VERSION 5.7 ;
  NOWIREEXTENSIONATPIN ON ;
  DIVIDERCHAR "/" ;
  BUSBITCHARS "[]" ;
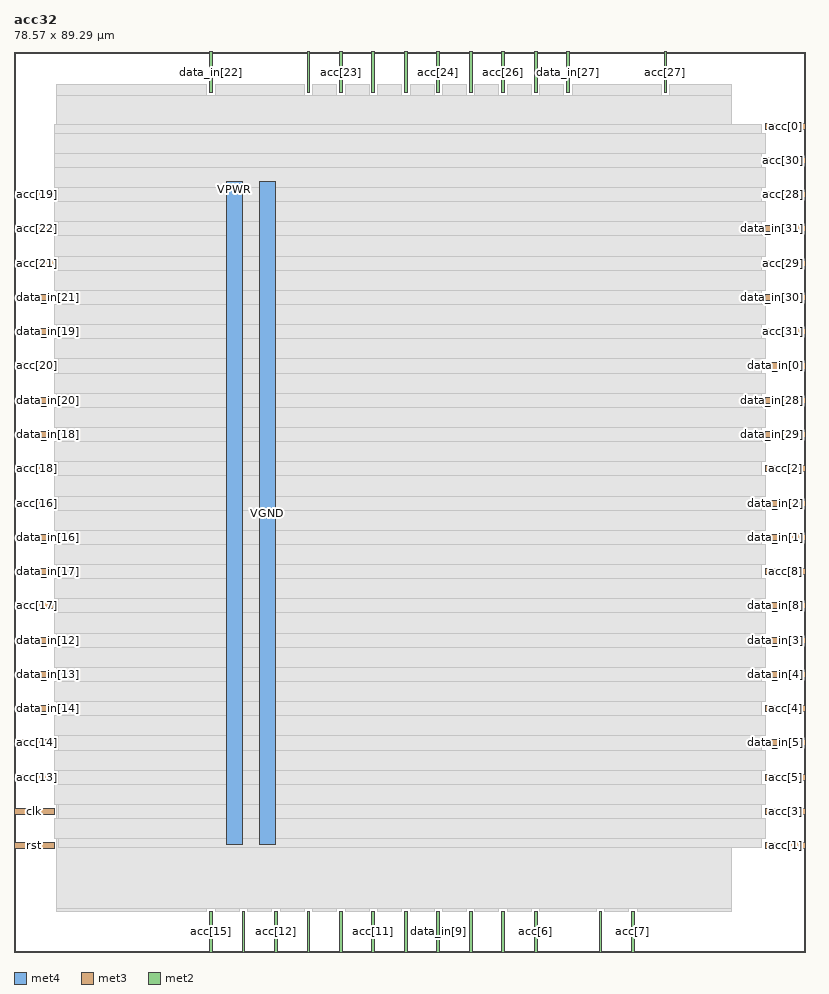
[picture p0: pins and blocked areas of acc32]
MACRO acc32
  CLASS BLOCK ;
  FOREIGN acc32 ;
  ORIGIN 0.000 0.000 ;
  SIZE 78.570 BY 89.290 ;
  PIN VGND
    DIRECTION INOUT ;
    USE GROUND ;
    PORT
      LAYER met4 ;
        RECT 24.340 10.640 25.940 76.400 ;
    END
  END VGND
  PIN VPWR
    DIRECTION INOUT ;
    USE POWER ;
    PORT
      LAYER met4 ;
        RECT 21.040 10.640 22.640 76.400 ;
    END
  END VPWR
  PIN acc[0]
    DIRECTION OUTPUT ;
    USE SIGNAL ;
    ANTENNADIFFAREA 0.445500 ;
    PORT
      LAYER met3 ;
        RECT 74.570 81.640 78.570 82.240 ;
    END
  END acc[0]
  PIN acc[10]
    DIRECTION OUTPUT ;
    USE SIGNAL ;
    ANTENNADIFFAREA 0.445500 ;
    PORT
      LAYER met2 ;
        RECT 29.070 0.000 29.350 4.000 ;
    END
  END acc[10]
  PIN acc[11]
    DIRECTION OUTPUT ;
    USE SIGNAL ;
    ANTENNADIFFAREA 0.445500 ;
    PORT
      LAYER met2 ;
        RECT 35.510 0.000 35.790 4.000 ;
    END
  END acc[11]
  PIN acc[12]
    DIRECTION OUTPUT ;
    USE SIGNAL ;
    ANTENNADIFFAREA 0.445500 ;
    PORT
      LAYER met2 ;
        RECT 25.850 0.000 26.130 4.000 ;
    END
  END acc[12]
  PIN acc[13]
    DIRECTION OUTPUT ;
    USE SIGNAL ;
    ANTENNADIFFAREA 0.445500 ;
    PORT
      LAYER met3 ;
        RECT 0.000 17.040 4.000 17.640 ;
    END
  END acc[13]
  PIN acc[14]
    DIRECTION OUTPUT ;
    USE SIGNAL ;
    ANTENNADIFFAREA 0.445500 ;
    PORT
      LAYER met3 ;
        RECT 0.000 20.440 4.000 21.040 ;
    END
  END acc[14]
  PIN acc[15]
    DIRECTION OUTPUT ;
    USE SIGNAL ;
    ANTENNADIFFAREA 0.445500 ;
    PORT
      LAYER met2 ;
        RECT 19.410 0.000 19.690 4.000 ;
    END
  END acc[15]
  PIN acc[16]
    DIRECTION OUTPUT ;
    USE SIGNAL ;
    ANTENNADIFFAREA 0.445500 ;
    PORT
      LAYER met3 ;
        RECT 0.000 44.240 4.000 44.840 ;
    END
  END acc[16]
  PIN acc[17]
    DIRECTION OUTPUT ;
    USE SIGNAL ;
    ANTENNADIFFAREA 0.445500 ;
    PORT
      LAYER met3 ;
        RECT 0.000 34.040 4.000 34.640 ;
    END
  END acc[17]
  PIN acc[18]
    DIRECTION OUTPUT ;
    USE SIGNAL ;
    ANTENNADIFFAREA 0.445500 ;
    PORT
      LAYER met3 ;
        RECT 0.000 47.640 4.000 48.240 ;
    END
  END acc[18]
  PIN acc[19]
    DIRECTION OUTPUT ;
    USE SIGNAL ;
    ANTENNADIFFAREA 0.445500 ;
    PORT
      LAYER met3 ;
        RECT 0.000 74.840 4.000 75.440 ;
    END
  END acc[19]
  PIN acc[1]
    DIRECTION OUTPUT ;
    USE SIGNAL ;
    ANTENNADIFFAREA 0.445500 ;
    PORT
      LAYER met3 ;
        RECT 74.570 10.240 78.570 10.840 ;
    END
  END acc[1]
  PIN acc[20]
    DIRECTION OUTPUT ;
    USE SIGNAL ;
    ANTENNADIFFAREA 0.445500 ;
    PORT
      LAYER met3 ;
        RECT 0.000 57.840 4.000 58.440 ;
    END
  END acc[20]
  PIN acc[21]
    DIRECTION OUTPUT ;
    USE SIGNAL ;
    ANTENNADIFFAREA 0.445500 ;
    PORT
      LAYER met3 ;
        RECT 0.000 68.040 4.000 68.640 ;
    END
  END acc[21]
  PIN acc[22]
    DIRECTION OUTPUT ;
    USE SIGNAL ;
    ANTENNADIFFAREA 0.445500 ;
    PORT
      LAYER met3 ;
        RECT 0.000 71.440 4.000 72.040 ;
    END
  END acc[22]
  PIN acc[23]
    DIRECTION OUTPUT ;
    USE SIGNAL ;
    ANTENNADIFFAREA 0.445500 ;
    PORT
      LAYER met2 ;
        RECT 32.290 85.290 32.570 89.290 ;
    END
  END acc[23]
  PIN acc[24]
    DIRECTION OUTPUT ;
    USE SIGNAL ;
    ANTENNADIFFAREA 0.445500 ;
    PORT
      LAYER met2 ;
        RECT 41.950 85.290 42.230 89.290 ;
    END
  END acc[24]
  PIN acc[25]
    DIRECTION OUTPUT ;
    USE SIGNAL ;
    ANTENNADIFFAREA 0.445500 ;
    PORT
      LAYER met2 ;
        RECT 35.510 85.290 35.790 89.290 ;
    END
  END acc[25]
  PIN acc[26]
    DIRECTION OUTPUT ;
    USE SIGNAL ;
    ANTENNADIFFAREA 0.445500 ;
    PORT
      LAYER met2 ;
        RECT 48.390 85.290 48.670 89.290 ;
    END
  END acc[26]
  PIN acc[27]
    DIRECTION OUTPUT ;
    USE SIGNAL ;
    ANTENNADIFFAREA 0.445500 ;
    PORT
      LAYER met2 ;
        RECT 64.490 85.290 64.770 89.290 ;
    END
  END acc[27]
  PIN acc[28]
    DIRECTION OUTPUT ;
    USE SIGNAL ;
    ANTENNADIFFAREA 0.445500 ;
    PORT
      LAYER met3 ;
        RECT 74.570 74.840 78.570 75.440 ;
    END
  END acc[28]
  PIN acc[29]
    DIRECTION OUTPUT ;
    USE SIGNAL ;
    ANTENNADIFFAREA 0.445500 ;
    PORT
      LAYER met3 ;
        RECT 74.570 68.040 78.570 68.640 ;
    END
  END acc[29]
  PIN acc[2]
    DIRECTION OUTPUT ;
    USE SIGNAL ;
    ANTENNADIFFAREA 0.445500 ;
    PORT
      LAYER met3 ;
        RECT 74.570 47.640 78.570 48.240 ;
    END
  END acc[2]
  PIN acc[30]
    DIRECTION OUTPUT ;
    USE SIGNAL ;
    ANTENNADIFFAREA 0.445500 ;
    PORT
      LAYER met3 ;
        RECT 74.570 78.240 78.570 78.840 ;
    END
  END acc[30]
  PIN acc[31]
    DIRECTION OUTPUT ;
    USE SIGNAL ;
    ANTENNADIFFAREA 0.445500 ;
    PORT
      LAYER met3 ;
        RECT 74.570 61.240 78.570 61.840 ;
    END
  END acc[31]
  PIN acc[3]
    DIRECTION OUTPUT ;
    USE SIGNAL ;
    ANTENNADIFFAREA 0.445500 ;
    PORT
      LAYER met3 ;
        RECT 74.570 13.640 78.570 14.240 ;
    END
  END acc[3]
  PIN acc[4]
    DIRECTION OUTPUT ;
    USE SIGNAL ;
    ANTENNADIFFAREA 0.445500 ;
    PORT
      LAYER met3 ;
        RECT 74.570 23.840 78.570 24.440 ;
    END
  END acc[4]
  PIN acc[5]
    DIRECTION OUTPUT ;
    USE SIGNAL ;
    ANTENNADIFFAREA 0.445500 ;
    PORT
      LAYER met3 ;
        RECT 74.570 17.040 78.570 17.640 ;
    END
  END acc[5]
  PIN acc[6]
    DIRECTION OUTPUT ;
    USE SIGNAL ;
    ANTENNADIFFAREA 0.445500 ;
    PORT
      LAYER met2 ;
        RECT 51.610 0.000 51.890 4.000 ;
    END
  END acc[6]
  PIN acc[7]
    DIRECTION OUTPUT ;
    USE SIGNAL ;
    ANTENNADIFFAREA 0.445500 ;
    PORT
      LAYER met2 ;
        RECT 61.270 0.000 61.550 4.000 ;
    END
  END acc[7]
  PIN acc[8]
    DIRECTION OUTPUT ;
    USE SIGNAL ;
    ANTENNADIFFAREA 0.445500 ;
    PORT
      LAYER met3 ;
        RECT 74.570 37.440 78.570 38.040 ;
    END
  END acc[8]
  PIN acc[9]
    DIRECTION OUTPUT ;
    USE SIGNAL ;
    ANTENNADIFFAREA 0.445500 ;
    PORT
      LAYER met2 ;
        RECT 45.170 0.000 45.450 4.000 ;
    END
  END acc[9]
  PIN clk
    DIRECTION INPUT ;
    USE SIGNAL ;
    ANTENNAGATEAREA 0.852000 ;
    PORT
      LAYER met3 ;
        RECT 0.000 13.640 4.000 14.240 ;
    END
  END clk
  PIN data_in[0]
    DIRECTION INPUT ;
    USE SIGNAL ;
    ANTENNAGATEAREA 0.196500 ;
    PORT
      LAYER met3 ;
        RECT 74.570 57.840 78.570 58.440 ;
    END
  END data_in[0]
  PIN data_in[10]
    DIRECTION INPUT ;
    USE SIGNAL ;
    ANTENNAGATEAREA 0.196500 ;
    PORT
      LAYER met2 ;
        RECT 32.290 0.000 32.570 4.000 ;
    END
  END data_in[10]
  PIN data_in[11]
    DIRECTION INPUT ;
    USE SIGNAL ;
    ANTENNAGATEAREA 0.196500 ;
    PORT
      LAYER met2 ;
        RECT 38.730 0.000 39.010 4.000 ;
    END
  END data_in[11]
  PIN data_in[12]
    DIRECTION INPUT ;
    USE SIGNAL ;
    ANTENNAGATEAREA 0.196500 ;
    PORT
      LAYER met3 ;
        RECT 0.000 30.640 4.000 31.240 ;
    END
  END data_in[12]
  PIN data_in[13]
    DIRECTION INPUT ;
    USE SIGNAL ;
    ANTENNAGATEAREA 0.196500 ;
    PORT
      LAYER met3 ;
        RECT 0.000 27.240 4.000 27.840 ;
    END
  END data_in[13]
  PIN data_in[14]
    DIRECTION INPUT ;
    USE SIGNAL ;
    ANTENNAGATEAREA 0.196500 ;
    PORT
      LAYER met3 ;
        RECT 0.000 23.840 4.000 24.440 ;
    END
  END data_in[14]
  PIN data_in[15]
    DIRECTION INPUT ;
    USE SIGNAL ;
    ANTENNAGATEAREA 0.196500 ;
    PORT
      LAYER met2 ;
        RECT 22.630 0.000 22.910 4.000 ;
    END
  END data_in[15]
  PIN data_in[16]
    DIRECTION INPUT ;
    USE SIGNAL ;
    ANTENNAGATEAREA 0.196500 ;
    PORT
      LAYER met3 ;
        RECT 0.000 40.840 4.000 41.440 ;
    END
  END data_in[16]
  PIN data_in[17]
    DIRECTION INPUT ;
    USE SIGNAL ;
    ANTENNAGATEAREA 0.196500 ;
    PORT
      LAYER met3 ;
        RECT 0.000 37.440 4.000 38.040 ;
    END
  END data_in[17]
  PIN data_in[18]
    DIRECTION INPUT ;
    USE SIGNAL ;
    ANTENNAGATEAREA 0.196500 ;
    PORT
      LAYER met3 ;
        RECT 0.000 51.040 4.000 51.640 ;
    END
  END data_in[18]
  PIN data_in[19]
    DIRECTION INPUT ;
    USE SIGNAL ;
    ANTENNAGATEAREA 0.196500 ;
    PORT
      LAYER met3 ;
        RECT 0.000 61.240 4.000 61.840 ;
    END
  END data_in[19]
  PIN data_in[1]
    DIRECTION INPUT ;
    USE SIGNAL ;
    ANTENNAGATEAREA 0.196500 ;
    PORT
      LAYER met3 ;
        RECT 74.570 40.840 78.570 41.440 ;
    END
  END data_in[1]
  PIN data_in[20]
    DIRECTION INPUT ;
    USE SIGNAL ;
    ANTENNAGATEAREA 0.196500 ;
    PORT
      LAYER met3 ;
        RECT 0.000 54.440 4.000 55.040 ;
    END
  END data_in[20]
  PIN data_in[21]
    DIRECTION INPUT ;
    USE SIGNAL ;
    ANTENNAGATEAREA 0.196500 ;
    PORT
      LAYER met3 ;
        RECT 0.000 64.640 4.000 65.240 ;
    END
  END data_in[21]
  PIN data_in[22]
    DIRECTION INPUT ;
    USE SIGNAL ;
    ANTENNAGATEAREA 0.196500 ;
    PORT
      LAYER met2 ;
        RECT 19.410 85.290 19.690 89.290 ;
    END
  END data_in[22]
  PIN data_in[23]
    DIRECTION INPUT ;
    USE SIGNAL ;
    ANTENNAGATEAREA 0.196500 ;
    PORT
      LAYER met2 ;
        RECT 29.070 85.290 29.350 89.290 ;
    END
  END data_in[23]
  PIN data_in[24]
    DIRECTION INPUT ;
    USE SIGNAL ;
    ANTENNAGATEAREA 0.196500 ;
    PORT
      LAYER met2 ;
        RECT 45.170 85.290 45.450 89.290 ;
    END
  END data_in[24]
  PIN data_in[25]
    DIRECTION INPUT ;
    USE SIGNAL ;
    ANTENNAGATEAREA 0.196500 ;
    PORT
      LAYER met2 ;
        RECT 38.730 85.290 39.010 89.290 ;
    END
  END data_in[25]
  PIN data_in[26]
    DIRECTION INPUT ;
    USE SIGNAL ;
    ANTENNAGATEAREA 0.196500 ;
    PORT
      LAYER met2 ;
        RECT 51.610 85.290 51.890 89.290 ;
    END
  END data_in[26]
  PIN data_in[27]
    DIRECTION INPUT ;
    USE SIGNAL ;
    ANTENNAGATEAREA 0.196500 ;
    PORT
      LAYER met2 ;
        RECT 54.830 85.290 55.110 89.290 ;
    END
  END data_in[27]
  PIN data_in[28]
    DIRECTION INPUT ;
    USE SIGNAL ;
    ANTENNAGATEAREA 0.196500 ;
    PORT
      LAYER met3 ;
        RECT 74.570 54.440 78.570 55.040 ;
    END
  END data_in[28]
  PIN data_in[29]
    DIRECTION INPUT ;
    USE SIGNAL ;
    ANTENNAGATEAREA 0.196500 ;
    PORT
      LAYER met3 ;
        RECT 74.570 51.040 78.570 51.640 ;
    END
  END data_in[29]
  PIN data_in[2]
    DIRECTION INPUT ;
    USE SIGNAL ;
    ANTENNAGATEAREA 0.196500 ;
    PORT
      LAYER met3 ;
        RECT 74.570 44.240 78.570 44.840 ;
    END
  END data_in[2]
  PIN data_in[30]
    DIRECTION INPUT ;
    USE SIGNAL ;
    ANTENNAGATEAREA 0.196500 ;
    PORT
      LAYER met3 ;
        RECT 74.570 64.640 78.570 65.240 ;
    END
  END data_in[30]
  PIN data_in[31]
    DIRECTION INPUT ;
    USE SIGNAL ;
    ANTENNAGATEAREA 0.196500 ;
    PORT
      LAYER met3 ;
        RECT 74.570 71.440 78.570 72.040 ;
    END
  END data_in[31]
  PIN data_in[3]
    DIRECTION INPUT ;
    USE SIGNAL ;
    ANTENNAGATEAREA 0.213000 ;
    PORT
      LAYER met3 ;
        RECT 74.570 30.640 78.570 31.240 ;
    END
  END data_in[3]
  PIN data_in[4]
    DIRECTION INPUT ;
    USE SIGNAL ;
    ANTENNAGATEAREA 0.196500 ;
    PORT
      LAYER met3 ;
        RECT 74.570 27.240 78.570 27.840 ;
    END
  END data_in[4]
  PIN data_in[5]
    DIRECTION INPUT ;
    USE SIGNAL ;
    ANTENNAGATEAREA 0.196500 ;
    PORT
      LAYER met3 ;
        RECT 74.570 20.440 78.570 21.040 ;
    END
  END data_in[5]
  PIN data_in[6]
    DIRECTION INPUT ;
    USE SIGNAL ;
    ANTENNAGATEAREA 0.196500 ;
    PORT
      LAYER met2 ;
        RECT 48.390 0.000 48.670 4.000 ;
    END
  END data_in[6]
  PIN data_in[7]
    DIRECTION INPUT ;
    USE SIGNAL ;
    ANTENNAGATEAREA 0.196500 ;
    PORT
      LAYER met2 ;
        RECT 58.050 0.000 58.330 4.000 ;
    END
  END data_in[7]
  PIN data_in[8]
    DIRECTION INPUT ;
    USE SIGNAL ;
    ANTENNAGATEAREA 0.196500 ;
    PORT
      LAYER met3 ;
        RECT 74.570 34.040 78.570 34.640 ;
    END
  END data_in[8]
  PIN data_in[9]
    DIRECTION INPUT ;
    USE SIGNAL ;
    ANTENNAGATEAREA 0.196500 ;
    PORT
      LAYER met2 ;
        RECT 41.950 0.000 42.230 4.000 ;
    END
  END data_in[9]
  PIN rst
    DIRECTION INPUT ;
    USE SIGNAL ;
    ANTENNAGATEAREA 0.126000 ;
    PORT
      LAYER met3 ;
        RECT 0.000 10.240 4.000 10.840 ;
    END
  END rst
  OBS
      LAYER nwell ;
        RECT 5.330 10.795 72.870 76.245 ;
      LAYER li1 ;
        RECT 5.520 10.795 72.680 76.245 ;
      LAYER met1 ;
        RECT 4.210 10.640 72.680 76.400 ;
      LAYER met2 ;
        RECT 4.230 85.010 19.130 86.090 ;
        RECT 19.970 85.010 28.790 86.090 ;
        RECT 29.630 85.010 32.010 86.090 ;
        RECT 32.850 85.010 35.230 86.090 ;
        RECT 36.070 85.010 38.450 86.090 ;
        RECT 39.290 85.010 41.670 86.090 ;
        RECT 42.510 85.010 44.890 86.090 ;
        RECT 45.730 85.010 48.110 86.090 ;
        RECT 48.950 85.010 51.330 86.090 ;
        RECT 52.170 85.010 54.550 86.090 ;
        RECT 55.390 85.010 64.210 86.090 ;
        RECT 65.050 85.010 71.210 86.090 ;
        RECT 4.230 4.280 71.210 85.010 ;
        RECT 4.230 4.000 19.130 4.280 ;
        RECT 19.970 4.000 22.350 4.280 ;
        RECT 23.190 4.000 25.570 4.280 ;
        RECT 26.410 4.000 28.790 4.280 ;
        RECT 29.630 4.000 32.010 4.280 ;
        RECT 32.850 4.000 35.230 4.280 ;
        RECT 36.070 4.000 38.450 4.280 ;
        RECT 39.290 4.000 41.670 4.280 ;
        RECT 42.510 4.000 44.890 4.280 ;
        RECT 45.730 4.000 48.110 4.280 ;
        RECT 48.950 4.000 51.330 4.280 ;
        RECT 52.170 4.000 57.770 4.280 ;
        RECT 58.610 4.000 60.990 4.280 ;
        RECT 61.830 4.000 71.210 4.280 ;
      LAYER met3 ;
        RECT 3.990 81.240 74.170 82.105 ;
        RECT 3.990 79.240 74.570 81.240 ;
        RECT 3.990 77.840 74.170 79.240 ;
        RECT 3.990 75.840 74.570 77.840 ;
        RECT 4.400 74.440 74.170 75.840 ;
        RECT 3.990 72.440 74.570 74.440 ;
        RECT 4.400 71.040 74.170 72.440 ;
        RECT 3.990 69.040 74.570 71.040 ;
        RECT 4.400 67.640 74.170 69.040 ;
        RECT 3.990 65.640 74.570 67.640 ;
        RECT 4.400 64.240 74.170 65.640 ;
        RECT 3.990 62.240 74.570 64.240 ;
        RECT 4.400 60.840 74.170 62.240 ;
        RECT 3.990 58.840 74.570 60.840 ;
        RECT 4.400 57.440 74.170 58.840 ;
        RECT 3.990 55.440 74.570 57.440 ;
        RECT 4.400 54.040 74.170 55.440 ;
        RECT 3.990 52.040 74.570 54.040 ;
        RECT 4.400 50.640 74.170 52.040 ;
        RECT 3.990 48.640 74.570 50.640 ;
        RECT 4.400 47.240 74.170 48.640 ;
        RECT 3.990 45.240 74.570 47.240 ;
        RECT 4.400 43.840 74.170 45.240 ;
        RECT 3.990 41.840 74.570 43.840 ;
        RECT 4.400 40.440 74.170 41.840 ;
        RECT 3.990 38.440 74.570 40.440 ;
        RECT 4.400 37.040 74.170 38.440 ;
        RECT 3.990 35.040 74.570 37.040 ;
        RECT 4.400 33.640 74.170 35.040 ;
        RECT 3.990 31.640 74.570 33.640 ;
        RECT 4.400 30.240 74.170 31.640 ;
        RECT 3.990 28.240 74.570 30.240 ;
        RECT 4.400 26.840 74.170 28.240 ;
        RECT 3.990 24.840 74.570 26.840 ;
        RECT 4.400 23.440 74.170 24.840 ;
        RECT 3.990 21.440 74.570 23.440 ;
        RECT 4.400 20.040 74.170 21.440 ;
        RECT 3.990 18.040 74.570 20.040 ;
        RECT 4.400 16.640 74.170 18.040 ;
        RECT 3.990 14.640 74.570 16.640 ;
        RECT 4.400 13.240 74.170 14.640 ;
        RECT 3.990 11.240 74.570 13.240 ;
        RECT 4.400 10.375 74.170 11.240 ;
  END
END acc32
END LIBRARY

